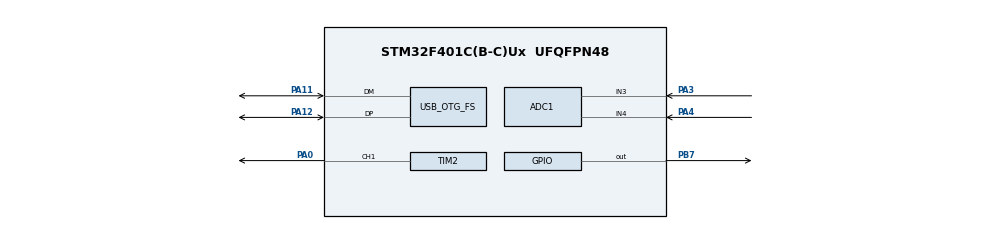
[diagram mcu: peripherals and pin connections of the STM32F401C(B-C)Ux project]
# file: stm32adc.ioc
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ADC1.Channel-7\#ChannelRegularConversion=ADC_CHANNEL_3
ADC1.Channel-8\#ChannelRegularConversion=ADC_CHANNEL_4
ADC1.ClockPrescaler=ADC_CLOCK_SYNC_PCLK_DIV8
ADC1.DMAContinuousRequests=ENABLE
ADC1.EOCSelection=ADC_EOC_SEQ_CONV
ADC1.NbrOfConversion=2
ADC1.NbrOfConversionFlag=1
ADC1.Rank-7\#ChannelRegularConversion=1
ADC1.Rank-8\#ChannelRegularConversion=2
ADC1.SamplingTime-7\#ChannelRegularConversion=ADC_SAMPLETIME_480CYCLES
ADC1.SamplingTime-8\#ChannelRegularConversion=ADC_SAMPLETIME_480CYCLES
ADC1.master=1
Dma.ADC1.0.Direction=DMA_PERIPH_TO_MEMORY
Dma.ADC1.0.FIFOMode=DMA_FIFOMODE_DISABLE
Dma.ADC1.0.Instance=DMA2_Stream0
Dma.ADC1.0.MemDataAlignment=DMA_MDATAALIGN_HALFWORD
Dma.ADC1.0.MemInc=DMA_MINC_ENABLE
Dma.ADC1.0.Mode=DMA_CIRCULAR
Dma.ADC1.0.PeriphDataAlignment=DMA_PDATAALIGN_HALFWORD
Dma.ADC1.0.PeriphInc=DMA_PINC_DISABLE
Dma.ADC1.0.Priority=DMA_PRIORITY_LOW
Dma.Request0=ADC1
Mcu.Family=STM32F4
Mcu.Name=STM32F401C(B-C)Ux
Mcu.Package=UFQFPN48
NVIC.DMA2_Stream0_IRQn=true\:0\:0\:false\:false\:true\:false\:true
NVIC.OTG_FS_IRQn=true\:0\:0\:false\:false\:true\:false\:true
NVIC.PriorityGroup=NVIC_PRIORITYGROUP_4
NVIC.TIM3_IRQn=true\:0\:0\:false\:false\:true\:true\:true
PA0-WKUP.Signal=S_TIM2_CH1_ETR
PA11.Mode=Device_Only
PA11.Signal=USB_OTG_FS_DM
PA12.Mode=Device_Only
PA12.Signal=USB_OTG_FS_DP
PA3.Signal=ADCx_IN3
PA4.Signal=ADCx_IN4
PB7.Signal=GPIO_Output
PH0\ -\ OSC_IN.Mode=HSE-External-Oscillator
PH0\ -\ OSC_IN.Signal=RCC_OSC_IN
PH1\ -\ OSC_OUT.Mode=HSE-External-Oscillator
PH1\ -\ OSC_OUT.Signal=RCC_OSC_OUT
ProjectManager.HeapSize=0x200
ProjectManager.StackSize=0x400
ProjectManager.TargetToolchain=STM32CubeIDE
RCC.48MHZClocksFreq_Value=48000000
RCC.AHBFreq_Value=84000000
RCC.APB1CLKDivider=RCC_HCLK_DIV2
RCC.APB1Freq_Value=42000000
RCC.APB1TimFreq_Value=84000000
RCC.APB2Freq_Value=84000000
RCC.APB2TimFreq_Value=84000000
RCC.CortexFreq_Value=84000000
RCC.HCLKFreq_Value=84000000
RCC.HSE_VALUE=25000000
RCC.HSI_VALUE=16000000
RCC.LSE_VALUE=32768
RCC.PLLM=25
RCC.PLLN=336
RCC.PLLP=RCC_PLLP_DIV4
RCC.PLLQ=7
RCC.SYSCLKFreq_VALUE=84000000
RCC.SYSCLKSource=RCC_SYSCLKSOURCE_PLLCLK
RCC.VCOOutputFreq_Value=336000000
SH.ADCx_IN3.0=ADC1_IN3,IN3
SH.ADCx_IN4.0=ADC1_IN4,IN4
SH.S_TIM2_CH1_ETR.0=TIM2_CH1,PWM Generation1 CH1
TIM2.Channel-PWM\ Generation1\ CH1=TIM_CHANNEL_1
TIM2.OCFastMode_PWM-PWM\ Generation1\ CH1=TIM_OCFAST_ENABLE
TIM2.Period=255
TIM2.Prescaler=1
TIM3.Period=420-1
TIM3.Prescaler=4-1
USB_DEVICE.CLASS_NAME_FS=CDC
USB_DEVICE.VirtualMode=Cdc
USB_DEVICE.VirtualModeFS=Cdc_FS
USB_OTG_FS.VirtualMode=Device_Only
VP_TIM2_VS_ClockSourceINT.Mode=Internal
VP_TIM3_VS_ClockSourceINT.Mode=Internal
VP_USB_DEVICE_VS_USB_DEVICE_CDC_FS.Mode=CDC_FS
board=custom

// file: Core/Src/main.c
/* USER CODE BEGIN Header */
/**
  ******************************************************************************
  * @file           : main.c
  * @brief          : Main program body
  ******************************************************************************
  * @attention
  *
  * Copyright (c) 2026 STMicroelectronics.
  * All rights reserved.
  *
  * This software is licensed under terms that can be found in the LICENSE file
  * in the root directory of this software component.
  * If no LICENSE file comes with this software, it is provided AS-IS.
  *
  ******************************************************************************
  */
/* USER CODE END Header */
#include "main.h"
#include "cmsis_os.h"
#include "usb_device.h"

/* USER CODE BEGIN Includes */
#include "usbd_cdc_if.h"
#include <math.h>
/* USER CODE END Includes */

ADC_HandleTypeDef hadc1;
DMA_HandleTypeDef hdma_adc1;

TIM_HandleTypeDef htim2;
TIM_HandleTypeDef htim3;

/* Definitions for defaultTask */
osThreadId_t defaultTaskHandle;
const osThreadAttr_t defaultTask_attributes = {
  .name = "defaultTask",
  .stack_size = 128 * 4,
  .priority = (osPriority_t) osPriorityNormal,
};
/* Definitions for myTask02 */
osThreadId_t myTask02Handle;
const osThreadAttr_t myTask02_attributes = {
  .name = "myTask02",
  .stack_size = 128 * 4,
  .priority = (osPriority_t) osPriorityLow,
};
/* Definitions for myTask03 */
osThreadId_t myTask03Handle;
const osThreadAttr_t myTask03_attributes = {
  .name = "myTask03",
  .stack_size = 128 * 4,
  .priority = (osPriority_t) osPriorityLow,
};
/* Definitions for myQueue01 */
osMessageQueueId_t myQueue01Handle;
const osMessageQueueAttr_t myQueue01_attributes = {
  .name = "myQueue01"
};
/* Definitions for myMutex01 */
osMutexId_t myMutex01Handle;
const osMutexAttr_t myMutex01_attributes = {
  .name = "myMutex01"
};
/* USER CODE BEGIN PV */
uint8_t dataPrint[100];
uint16_t dataPrintLen = 0;
uint16_t ADCStatus = 0;
volatile uint16_t adc_buffer[5];
uint8_t serial_send(const uint8_t * data, const uint16_t len);

void HAL_ADC_ConvCpltCallback(ADC_HandleTypeDef* hadc) {
	if(hadc->Instance == ADC1) {
		//ADCStatus = 1;
		osStatus_t status = osMessageQueuePut(myQueue01Handle, &adc_buffer[0], 0U, 0U);
		if (status != osOK) {
		    // Handle error (e.g., queue full)
		}
	}
}
/* USER CODE END PV */

void SystemClock_Config(void);
static void MX_GPIO_Init(void);
static void MX_ADC1_Init(void);
static void MX_DMA_Init(void);
static void MX_TIM2_Init(void);
static void MX_TIM3_Init(void);
void StartDefaultTask(void *argument);
void StartTask02(void *argument);
void StartTask03(void *argument);

/* USER CODE BEGIN 0 */

uint8_t serial_send(const uint8_t * data, const uint16_t len){
   if (data == NULL) {
       return 0;
   }

   CDC_Transmit_FS(data, len);

   return 1;
}
uint8_t data[100] = "Hello world!\n";
uint16_t len;

/* USER CODE END 0 */

int main(void)
{

  /* MCU Configuration--------------------------------------------------------*/

  /* Reset of all peripherals, Initializes the Flash interface and the Systick. */
  HAL_Init();

  /* Configure the system clock */
  SystemClock_Config();

  /* Initialize all configured peripherals */
  MX_GPIO_Init();
  MX_DMA_Init();
  MX_TIM2_Init();
  MX_TIM3_Init();
  MX_ADC1_Init();
  /* USER CODE BEGIN 2 */
  HAL_TIM_Base_Start_IT(&htim3);
  HAL_TIM_PWM_Start(&htim2, TIM_CHANNEL_1);
  __HAL_TIM_SET_COMPARE(&htim2, TIM_CHANNEL_1, 124);

  /* USER CODE END 2 */

  /* Init scheduler */
  osKernelInitialize();
  /* Create the mutex(es) */
  /* creation of myMutex01 */
  myMutex01Handle = osMutexNew(&myMutex01_attributes);

  /* Create the queue(s) */
  /* creation of myQueue01 */
  myQueue01Handle = osMessageQueueNew (16, sizeof(uint16_t), &myQueue01_attributes);

  /* Create the thread(s) */
  /* creation of defaultTask */
  defaultTaskHandle = osThreadNew(StartDefaultTask, NULL, &defaultTask_attributes);

  /* creation of myTask02 */
  myTask02Handle = osThreadNew(StartTask02, NULL, &myTask02_attributes);

  /* creation of myTask03 */
  myTask03Handle = osThreadNew(StartTask03, NULL, &myTask03_attributes);

  /* USER CODE BEGIN RTOS_THREADS */
  HAL_ADC_Start_DMA(&hadc1, (uint32_t*)adc_buffer, 5);
  /* add threads, ... */
  /* USER CODE END RTOS_THREADS */

  /* Start scheduler */
  osKernelStart();

  /* We should never get here as control is now taken by the scheduler */
  /* Infinite loop */
  /* USER CODE BEGIN WHILE */
  len = strlen(data);
  //uint16_t ledOnTyme = 0;
 // int i = 0;
  HAL_ADC_Start_DMA(&hadc1, (uint32_t*)adc_buffer, 5);
  while (1)
  {
	  /*
      if (ADCStatus) {
	    sprintf(dataPrint,"ADC 0: %d\n",adc_buffer[0]);
	  	serial_send(dataPrint, strlen(dataPrint));
	  	HAL_Delay(100);
	  	sprintf(dataPrint,"ADC 1: %d\n",adc_buffer[1]);
	  	serial_send(dataPrint, strlen(dataPrint));
	  	HAL_Delay(100);
	  	sprintf(dataPrint,"ADC 2: %d\n",adc_buffer[2]);
	  	serial_send(dataPrint, strlen(dataPrint));
	  	HAL_Delay(100);
	  	sprintf(dataPrint,"ADC 3: %d\n",adc_buffer[3]);
	    serial_send(dataPrint, strlen(dataPrint));
	  	HAL_Delay(100);
	  	sprintf(dataPrint,"ADC 4: %d\n\n",adc_buffer[4]);
	  	serial_send(dataPrint, strlen(dataPrint));
	  	HAL_Delay(100);
	  	ADCStatus = 0;
	  	HAL_ADC_Start_DMA(&hadc1, (uint32_t*)adc_buffer, 5);
      }
	 HAL_Delay(1000);
*/
    /* USER CODE END WHILE */

  }
}

void SystemClock_Config(void)
{
  RCC_OscInitTypeDef RCC_OscInitStruct = {0};
  RCC_ClkInitTypeDef RCC_ClkInitStruct = {0};

  /** Configure the main internal regulator output voltage
  */
  __HAL_RCC_PWR_CLK_ENABLE();
  __HAL_PWR_VOLTAGESCALING_CONFIG(PWR_REGULATOR_VOLTAGE_SCALE2);
  /** Initializes the RCC Oscillators according to the specified parameters
  * in the RCC_OscInitTypeDef structure.
  */
  RCC_OscInitStruct.OscillatorType = RCC_OSCILLATORTYPE_HSE;
  RCC_OscInitStruct.HSEState = RCC_HSE_ON;
  RCC_OscInitStruct.PLL.PLLState = RCC_PLL_ON;
  RCC_OscInitStruct.PLL.PLLSource = RCC_PLLSOURCE_HSE;
  RCC_OscInitStruct.PLL.PLLM = 25;
  RCC_OscInitStruct.PLL.PLLN = 336;
  RCC_OscInitStruct.PLL.PLLP = RCC_PLLP_DIV4;
  RCC_OscInitStruct.PLL.PLLQ = 7;
  if (HAL_RCC_OscConfig(&RCC_OscInitStruct) != HAL_OK)
  {
    Error_Handler();
  }
  /** Initializes the CPU, AHB and APB buses clocks
  */
  RCC_ClkInitStruct.ClockType = RCC_CLOCKTYPE_HCLK|RCC_CLOCKTYPE_SYSCLK
                              |RCC_CLOCKTYPE_PCLK1|RCC_CLOCKTYPE_PCLK2;
  RCC_ClkInitStruct.SYSCLKSource = RCC_SYSCLKSOURCE_PLLCLK;
  RCC_ClkInitStruct.AHBCLKDivider = RCC_SYSCLK_DIV1;
  RCC_ClkInitStruct.APB1CLKDivider = RCC_HCLK_DIV16;
  RCC_ClkInitStruct.APB2CLKDivider = RCC_HCLK_DIV1;

  if (HAL_RCC_ClockConfig(&RCC_ClkInitStruct, FLASH_LATENCY_2) != HAL_OK)
  {
    Error_Handler();
  }
}

static void MX_ADC1_Init(void)
{

  ADC_ChannelConfTypeDef sConfig = {0};

  /** Configure the global features of the ADC (Clock, Resolution, Data Alignment and number of conversion)
  */
  hadc1.Instance = ADC1;
  hadc1.Init.ClockPrescaler = ADC_CLOCK_SYNC_PCLK_DIV8;
  hadc1.Init.Resolution = ADC_RESOLUTION_12B;
  hadc1.Init.ScanConvMode = ENABLE;
  hadc1.Init.ContinuousConvMode = DISABLE;
  hadc1.Init.DiscontinuousConvMode = DISABLE;
  hadc1.Init.ExternalTrigConvEdge = ADC_EXTERNALTRIGCONVEDGE_NONE;
  hadc1.Init.ExternalTrigConv = ADC_SOFTWARE_START;
  hadc1.Init.DataAlign = ADC_DATAALIGN_RIGHT;
  hadc1.Init.NbrOfConversion = 5;
  hadc1.Init.DMAContinuousRequests = ENABLE;
  hadc1.Init.EOCSelection = ADC_EOC_SEQ_CONV;
  if (HAL_ADC_Init(&hadc1) != HAL_OK)
  {
    Error_Handler();
  }
  /** Configure for the selected ADC regular channel its corresponding rank in the sequencer and its sample time.
  */
  sConfig.Channel = ADC_CHANNEL_0;
  sConfig.Rank = 1;
  sConfig.SamplingTime = ADC_SAMPLETIME_480CYCLES;
  if (HAL_ADC_ConfigChannel(&hadc1, &sConfig) != HAL_OK)
  {
    Error_Handler();
  }
  /** Configure for the selected ADC regular channel its corresponding rank in the sequencer and its sample time.
  */
  sConfig.Channel = ADC_CHANNEL_1;
  sConfig.Rank = 2;
  if (HAL_ADC_ConfigChannel(&hadc1, &sConfig) != HAL_OK)
  {
    Error_Handler();
  }
  /** Configure for the selected ADC regular channel its corresponding rank in the sequencer and its sample time.
  */
  sConfig.Channel = ADC_CHANNEL_2;
  sConfig.Rank = 3;
  sConfig.SamplingTime = ADC_SAMPLETIME_3CYCLES;
  if (HAL_ADC_ConfigChannel(&hadc1, &sConfig) != HAL_OK)
  {
    Error_Handler();
  }
  /** Configure for the selected ADC regular channel its corresponding rank in the sequencer and its sample time.
  */
  sConfig.Channel = ADC_CHANNEL_3;
  sConfig.Rank = 4;
  if (HAL_ADC_ConfigChannel(&hadc1, &sConfig) != HAL_OK)
  {
    Error_Handler();
  }
  /** Configure for the selected ADC regular channel its corresponding rank in the sequencer and its sample time.
  */
  sConfig.Channel = ADC_CHANNEL_4;
  sConfig.Rank = 5;
  if (HAL_ADC_ConfigChannel(&hadc1, &sConfig) != HAL_OK)
  {
    Error_Handler();
  }

}

static void MX_TIM2_Init(void)
{

  TIM_ClockConfigTypeDef sClockSourceConfig = {0};
  TIM_MasterConfigTypeDef sMasterConfig = {0};
  TIM_OC_InitTypeDef sConfigOC = {0};

  htim2.Instance = TIM2;
  htim2.Init.Prescaler = 1;
  htim2.Init.CounterMode = TIM_COUNTERMODE_UP;
  htim2.Init.Period = 255;
  htim2.Init.ClockDivision = TIM_CLOCKDIVISION_DIV1;
  htim2.Init.AutoReloadPreload = TIM_AUTORELOAD_PRELOAD_DISABLE;
  if (HAL_TIM_Base_Init(&htim2) != HAL_OK)
  {
    Error_Handler();
  }
  sClockSourceConfig.ClockSource = TIM_CLOCKSOURCE_INTERNAL;
  if (HAL_TIM_ConfigClockSource(&htim2, &sClockSourceConfig) != HAL_OK)
  {
    Error_Handler();
  }
  if (HAL_TIM_PWM_Init(&htim2) != HAL_OK)
  {
    Error_Handler();
  }
  sMasterConfig.MasterOutputTrigger = TIM_TRGO_RESET;
  sMasterConfig.MasterSlaveMode = TIM_MASTERSLAVEMODE_DISABLE;
  if (HAL_TIMEx_MasterConfigSynchronization(&htim2, &sMasterConfig) != HAL_OK)
  {
    Error_Handler();
  }
  sConfigOC.OCMode = TIM_OCMODE_PWM1;
  sConfigOC.Pulse = 0;
  sConfigOC.OCPolarity = TIM_OCPOLARITY_HIGH;
  sConfigOC.OCFastMode = TIM_OCFAST_ENABLE;
  if (HAL_TIM_PWM_ConfigChannel(&htim2, &sConfigOC, TIM_CHANNEL_1) != HAL_OK)
  {
    Error_Handler();
  }
  HAL_TIM_MspPostInit(&htim2);

}

static void MX_TIM3_Init(void)
{

  TIM_ClockConfigTypeDef sClockSourceConfig = {0};
  TIM_MasterConfigTypeDef sMasterConfig = {0};

  htim3.Instance = TIM3;
  htim3.Init.Prescaler = 4-1;
  htim3.Init.CounterMode = TIM_COUNTERMODE_UP;
  htim3.Init.Period = 420-1;
  htim3.Init.ClockDivision = TIM_CLOCKDIVISION_DIV1;
  htim3.Init.AutoReloadPreload = TIM_AUTORELOAD_PRELOAD_DISABLE;
  if (HAL_TIM_Base_Init(&htim3) != HAL_OK)
  {
    Error_Handler();
  }
  sClockSourceConfig.ClockSource = TIM_CLOCKSOURCE_INTERNAL;
  if (HAL_TIM_ConfigClockSource(&htim3, &sClockSourceConfig) != HAL_OK)
  {
    Error_Handler();
  }
  sMasterConfig.MasterOutputTrigger = TIM_TRGO_RESET;
  sMasterConfig.MasterSlaveMode = TIM_MASTERSLAVEMODE_DISABLE;
  if (HAL_TIMEx_MasterConfigSynchronization(&htim3, &sMasterConfig) != HAL_OK)
  {
    Error_Handler();
  }

}

static void MX_DMA_Init(void)
{

  /* DMA controller clock enable */
  __HAL_RCC_DMA2_CLK_ENABLE();

  /* DMA interrupt init */
  /* DMA2_Stream0_IRQn interrupt configuration */
  HAL_NVIC_SetPriority(DMA2_Stream0_IRQn, 5, 0);
  HAL_NVIC_EnableIRQ(DMA2_Stream0_IRQn);

}

static void MX_GPIO_Init(void)
{
  GPIO_InitTypeDef GPIO_InitStruct = {0};

  /* GPIO Ports Clock Enable */
  __HAL_RCC_GPIOH_CLK_ENABLE();
  __HAL_RCC_GPIOA_CLK_ENABLE();
  __HAL_RCC_GPIOB_CLK_ENABLE();

  /*Configure GPIO pin Output Level */
  HAL_GPIO_WritePin(GPIOB, GPIO_PIN_7, GPIO_PIN_RESET);

  /*Configure GPIO pin : PB7 */
  GPIO_InitStruct.Pin = GPIO_PIN_7;
  GPIO_InitStruct.Mode = GPIO_MODE_OUTPUT_PP;
  GPIO_InitStruct.Pull = GPIO_NOPULL;
  GPIO_InitStruct.Speed = GPIO_SPEED_FREQ_LOW;
  HAL_GPIO_Init(GPIOB, &GPIO_InitStruct);

}

void StartDefaultTask(void *argument)
{
  /* init code for USB_DEVICE */
  MX_USB_DEVICE_Init();
  for(;;)
  {
    osDelay(1);
  }
}

void StartTask02(void *argument)
{
  /* USER CODE BEGIN StartTask02 */
  /* Infinite loop */
  for(;;)
  {
	uint16_t adcData;

	osStatus_t status = osMessageQueueGet(myQueue01Handle, &adcData, NULL, osWaitForever);
	if (status == osOK)
	{
		sprintf(dataPrint,"ADC 0: %d\n",adcData);
		serial_send(dataPrint, strlen(dataPrint));
	}
    osDelay(1000);
	HAL_ADC_Start_DMA(&hadc1, (uint32_t*)adc_buffer, 5);
  }
  /* USER CODE END StartTask02 */
}

void StartTask03(void *argument)
{
  for(;;)
  {
    osDelay(1);
  }
}

void HAL_TIM_PeriodElapsedCallback(TIM_HandleTypeDef *htim)
{
  if (htim->Instance == TIM1) {
    HAL_IncTick();
  }
}

void Error_Handler(void)
{
  __disable_irq();
  while (1)
  {
  }
}
